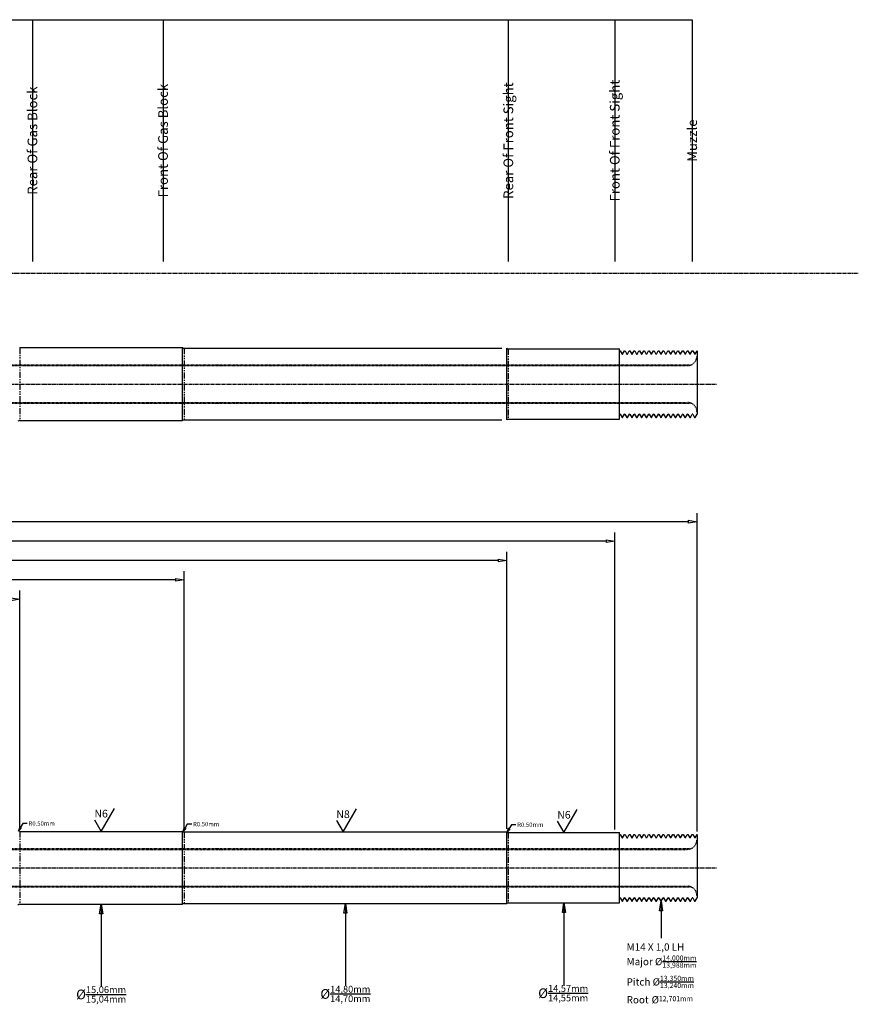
# Model space of a CAD drawing. Units: inches. Extents: x -1 to 483, y -54 to 185.
# Drawn here: x 310 to 483, y -18 to 185 of the extents above; entities that cross this region are included whole.
import ezdxf
from ezdxf.enums import TextEntityAlignment as Align

# ---------------------------------------------------------------- set-up
doc = ezdxf.new("R2010")
doc.units = ezdxf.units.IN
doc.header["$MEASUREMENT"] = 0
for name, pattern in [('CENTER2', [1.125, 0.75, -0.125, 0.125, -0.125]), ('HIDDEN2', [0.1875, 0.125, -0.0625]), ('PHANTOM', [2.5, 1.25, -0.25, 0.25, -0.25, 0.25, -0.25])]:
    doc.linetypes.add(name, pattern=pattern)
for name, color, linetype in [('CENTERLINE', 1, 'CENTER2'), ('HIDDEN', 5, 'HIDDEN2'), ('PHANTOM', 252, 'PHANTOM'), ('TEXT', 5, 'Continuous')]:
    doc.layers.add(name, color=color, linetype=linetype)
doc.dimstyles.get("Standard").update_dxf_attribs({"dimtxt": 0.18, "dimasz": 0.18, "dimexe": 0.18, "dimexo": 0.0625, "dimgap": 0.09, "dimtad": 0, "dimtih": 1, "dimtoh": 1, "dimdec": 4, "dimzin": 0, "dimdsep": 46, "dimtxsty": 'Standard', "dimcen": 0.09, "dimadec": 0, "dimazin": 0, "dimtfac": 1, "dimtdec": 4, "dimtofl": 0, "dimtmove": 0, "dimatfit": 3, "dimfxl": 0, "dimtolj": 1, "dimtzin": 0, "dimarcsym": 0})
doc.dimstyles.new('Standard$0', dxfattribs={"dimtxt": 0.18, "dimasz": 0.18, "dimexe": 0.18, "dimexo": 0.0625, "dimgap": 0.09, "dimtad": 0, "dimtih": 1, "dimtoh": 1, "dimdec": 4, "dimzin": 4, "dimdsep": 46, "dimtxsty": 'Standard', "dimcen": 0.09, "dimadec": 5, "dimazin": 1, "dimtfac": 1, "dimtdec": 4, "dimtofl": 0, "dimtmove": 0, "dimatfit": 3, "dimfxl": 0, "dimtolj": 1, "dimtzin": 0, "dimarcsym": 0})

# ---------------------------------------------------------------- blocks, each defined once
blk = doc.blocks.new('_ClosedBlank')
at = {"color": 0, "linetype": 'ByBlock', "lineweight": -2}
for p, q in [((-1, 0.17), (0, 0)), ((-1, 0.17), (-1, -0.17)), ((0, 0), (-1, -0.17))]:
    blk.add_line(p, q, dxfattribs=at)
blk = doc.blocks.new('*D12')
at = {"color": 0, "lineweight": -2}
for p, q in [((34.79, 20.8), (34.79, 83.23)), ((36.59, 81.43), (236.44, 81.43)), ((447.99, 81.43), (248.14, 81.43)), ((449.79, 17.42), (449.79, 83.23))]:
    blk.add_line(p, q, dxfattribs=at)
at = {"layer": 'Defpoints', "color": 0}
for p in [(449.79, 81.43), (34.79, 20.18), (449.79, 16.8)]:
    blk.add_point(p, dxfattribs=at)
at = {"color": 0, "lineweight": -2, "xscale": 1.8, "yscale": 1.8, "zscale": 1.8, "rotation": 180}
blk.add_blockref('_ClosedBlank', (34.79, 81.43), dxfattribs=at)
at = {"color": 0, "lineweight": -2, "xscale": 1.8, "yscale": 1.8, "zscale": 1.8}
blk.add_blockref('_ClosedBlank', (449.79, 81.43), dxfattribs=at)
at = {"color": 0, "insert": (242.29, 81.43), "char_height": 1.8, "attachment_point": 5}
blk.add_mtext('\\A1;415.0mm', dxfattribs=at)
blk = doc.blocks.new('*D7')
at = {"color": 0, "lineweight": -2}
for p, q in [((34.79, 20.8), (34.79, 67.23)), ((309.79, 18.06), (309.79, 67.23)), ((36.59, 65.43), (166.14, 65.43)), ((307.99, 65.43), (178.44, 65.43))]:
    blk.add_line(p, q, dxfattribs=at)
at = {"layer": 'Defpoints', "color": 0}
for p in [(34.79, 65.43), (34.79, 20.18), (309.79, 17.43)]:
    blk.add_point(p, dxfattribs=at)
at = {"color": 0, "lineweight": -2, "xscale": 1.8, "yscale": 1.8, "zscale": 1.8, "rotation": 180}
blk.add_blockref('_ClosedBlank', (34.79, 65.43), dxfattribs=at)
at = {"color": 0, "lineweight": -2, "xscale": 1.8, "yscale": 1.8, "zscale": 1.8}
blk.add_blockref('_ClosedBlank', (309.79, 65.43), dxfattribs=at)
at = {"color": 0, "insert": (172.29, 65.43), "char_height": 1.8, "attachment_point": 5}
blk.add_mtext('\\A1;275.0mm', dxfattribs=at)
blk = doc.blocks.new('*D8')
at = {"color": 0, "lineweight": -2}
for p, q in [((34.79, 20.8), (34.79, 71.23)), ((36.59, 69.43), (183.29, 69.43)), ((341.99, 69.43), (195.29, 69.43)), ((343.79, 17.93), (343.79, 71.23))]:
    blk.add_line(p, q, dxfattribs=at)
at = {"layer": 'Defpoints', "color": 0}
for p in [(34.79, 69.43), (34.79, 20.18), (343.79, 17.31)]:
    blk.add_point(p, dxfattribs=at)
at = {"color": 0, "lineweight": -2, "xscale": 1.8, "yscale": 1.8, "zscale": 1.8, "rotation": 180}
blk.add_blockref('_ClosedBlank', (34.79, 69.43), dxfattribs=at)
at = {"color": 0, "lineweight": -2, "xscale": 1.8, "yscale": 1.8, "zscale": 1.8}
blk.add_blockref('_ClosedBlank', (343.79, 69.43), dxfattribs=at)
at = {"color": 0, "insert": (189.29, 69.43), "char_height": 1.8, "attachment_point": 5}
blk.add_mtext('\\A1;309.0mm', dxfattribs=at)
blk = doc.blocks.new('*D9')
at = {"color": 0, "lineweight": -2}
for p, q in [((34.79, 20.8), (34.79, 75.23)), ((36.59, 73.43), (216.33, 73.43)), ((408.66, 73.43), (228.93, 73.43)), ((410.46, 17.93), (410.46, 75.23))]:
    blk.add_line(p, q, dxfattribs=at)
at = {"layer": 'Defpoints', "color": 0}
for p in [(34.79, 73.43), (34.79, 20.18), (410.46, 17.31)]:
    blk.add_point(p, dxfattribs=at)
at = {"color": 0, "lineweight": -2, "xscale": 1.8, "yscale": 1.8, "zscale": 1.8, "rotation": 180}
blk.add_blockref('_ClosedBlank', (34.79, 73.43), dxfattribs=at)
at = {"color": 0, "lineweight": -2, "xscale": 1.8, "yscale": 1.8, "zscale": 1.8}
blk.add_blockref('_ClosedBlank', (410.46, 73.43), dxfattribs=at)
at = {"color": 0, "insert": (222.63, 73.43), "char_height": 1.8, "attachment_point": 5}
blk.add_mtext('\\A1;375.7mm', dxfattribs=at)
blk = doc.blocks.new('*D10')
at = {"color": 0, "lineweight": -2}
for p, q in [((34.79, 20.8), (34.79, 79.23)), ((36.59, 77.43), (227.64, 77.43)), ((430.99, 77.43), (239.94, 77.43)), ((432.79, 17.81), (432.79, 79.23))]:
    blk.add_line(p, q, dxfattribs=at)
at = {"layer": 'Defpoints', "color": 0}
for p in [(432.79, 77.43), (34.79, 20.18), (432.79, 17.18)]:
    blk.add_point(p, dxfattribs=at)
at = {"color": 0, "lineweight": -2, "xscale": 1.8, "yscale": 1.8, "zscale": 1.8, "rotation": 180}
blk.add_blockref('_ClosedBlank', (34.79, 77.43), dxfattribs=at)
at = {"color": 0, "lineweight": -2, "xscale": 1.8, "yscale": 1.8, "zscale": 1.8}
blk.add_blockref('_ClosedBlank', (432.79, 77.43), dxfattribs=at)
at = {"color": 0, "insert": (233.79, 77.43), "char_height": 1.8, "attachment_point": 5}
blk.add_mtext('\\A1;398.0mm', dxfattribs=at)
blk = doc.blocks.new('*D21')
at = {"color": 0, "lineweight": -2}
for p, q in [((310.44, 19.06), (309.99, 18.28)), ((311.34, 19.06), (310.44, 19.06))]:
    blk.add_line(p, q, dxfattribs=at)
at = {"layer": 'Defpoints', "color": 0}
for p in [(309.54, 17.5), (309.79, 17.93)]:
    blk.add_point(p, dxfattribs=at)
at = {"color": 0, "lineweight": -2, "xscale": 0.8999999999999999, "yscale": 0.8999999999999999, "zscale": 0.8999999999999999, "rotation": 240.0000000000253}
blk.add_blockref('_ClosedBlank', (309.54, 17.5), dxfattribs=at)
at = {"color": 0, "insert": (314.34, 19.06), "char_height": 0.9, "attachment_point": 5}
blk.add_mtext('\\A1;R0.50mm', dxfattribs=at)
blk = doc.blocks.new('*D22')
at = {"color": 0, "lineweight": -2}
for p, q in [((344.44, 18.93), (343.99, 18.15)), ((345.34, 18.93), (344.44, 18.93))]:
    blk.add_line(p, q, dxfattribs=at)
at = {"layer": 'Defpoints', "color": 0}
for p in [(343.54, 17.37), (343.79, 17.81)]:
    blk.add_point(p, dxfattribs=at)
at = {"color": 0, "lineweight": -2, "xscale": 0.8999999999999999, "yscale": 0.8999999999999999, "zscale": 0.8999999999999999, "rotation": 240.0000000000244}
blk.add_blockref('_ClosedBlank', (343.54, 17.37), dxfattribs=at)
at = {"color": 0, "insert": (348.34, 18.93), "char_height": 0.9, "attachment_point": 5}
blk.add_mtext('\\A1;R0.50mm', dxfattribs=at)
blk = doc.blocks.new('*D23')
at = {"color": 0, "lineweight": -2}
for p, q in [((411.44, 18.81), (410.99, 18.03)), ((412.34, 18.81), (411.44, 18.81))]:
    blk.add_line(p, q, dxfattribs=at)
at = {"layer": 'Defpoints', "color": 0}
for p in [(410.54, 17.25), (410.79, 17.68)]:
    blk.add_point(p, dxfattribs=at)
at = {"color": 0, "lineweight": -2, "xscale": 0.8999999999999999, "yscale": 0.8999999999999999, "zscale": 0.8999999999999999, "rotation": 239.9999999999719}
blk.add_blockref('_ClosedBlank', (410.54, 17.25), dxfattribs=at)
at = {"color": 0, "insert": (415.34, 18.81), "char_height": 0.9, "attachment_point": 5}
blk.add_mtext('\\A1;R0.50mm', dxfattribs=at)

msp = doc.modelspace()

# ---------------------------------------------------------------- linework, layer by layer
for p, q in [((6.79168, 185.23005), (448.79168, 185.23005)), ((312.42168, 185.23005), (312.42168, 135.23005)), ((339.42168, 185.23005), (339.42168, 135.23005)), ((410.79168, 185.23005), (410.79168, 135.23005)), ((432.79168, 185.23005), (432.79168, 135.23005)), ((448.79168, 185.23005), (448.79168, 135.23005)), ((309.79168, 117.43025), (343.46096, 117.43025)), ((343.46096, 102.38025), (343.46096, 117.43025)), ((343.79168, 117.30525), (409.46096, 117.30525)), ((410.46096, 102.50525), (410.46096, 117.30525)), ((410.79168, 117.18025), (433.79168, 117.18025)), ((433.79168, 102.63025), (433.79168, 117.18025)), ((433.79168, 116.79699), (433.91668, 116.79699)), ((433.91668, 116.79699), (434.31251, 116.11139)), ((434.29168, 116.14747), (434.31251, 116.11139)), ((434.31251, 116.11139), (434.39585, 116.11139)), ((434.39585, 116.11139), (434.31251, 116.11139)), ((434.39585, 116.11139), (434.79168, 116.79699)), ((434.79168, 116.79699), (434.91668, 116.79699)), ((434.91668, 116.79699), (435.31251, 116.11139)), ((435.29168, 116.14747), (435.31251, 116.11139)), ((435.31251, 116.11139), (435.39585, 116.11139)), ((435.39585, 116.11139), (435.31251, 116.11139)), ((435.39585, 116.11139), (435.79168, 116.79699)), ((435.79168, 116.79699), (435.91668, 116.79699)), ((435.91668, 116.79699), (436.31251, 116.11139)), ((436.29168, 116.14747), (436.31251, 116.11139)), ((436.31251, 116.11139), (436.39585, 116.11139)), ((436.39585, 116.11139), (436.31251, 116.11139)), ((436.39585, 116.11139), (436.79168, 116.79699)), ((436.79168, 116.79699), (436.91668, 116.79699)), ((436.91668, 116.79699), (437.31251, 116.11139)), ((437.29168, 116.14747), (437.31251, 116.11139)), ((437.31251, 116.11139), (437.39585, 116.11139)), ((437.39585, 116.11139), (437.31251, 116.11139)), ((437.39585, 116.11139), (437.79168, 116.79699)), ((437.79168, 116.79699), (437.91668, 116.79699)), ((437.91668, 116.79699), (438.31251, 116.11139)), ((438.31251, 116.11139), (438.39585, 116.11139)), ((438.39585, 116.11139), (438.31251, 116.11139)), ((438.39585, 116.11139), (438.79168, 116.79699)), ((438.79168, 116.79699), (438.91668, 116.79699)), ((438.91668, 116.79699), (439.31251, 116.11139)), ((439.39585, 116.11139), (439.31251, 116.11139)), ((439.39585, 116.11139), (439.79168, 116.79699)), ((439.79168, 116.79699), (439.91668, 116.79699)), ((439.91668, 116.79699), (440.31251, 116.11139)), ((440.39585, 116.11139), (440.31251, 116.11139)), ((440.39585, 116.11139), (440.79168, 116.79699)), ((440.79168, 116.79699), (440.91668, 116.79699)), ((440.91668, 116.79699), (441.31251, 116.11139)), ((441.39585, 116.11139), (441.31251, 116.11139)), ((441.39585, 116.11139), (441.79168, 116.79699)), ((441.79168, 116.79699), (441.91668, 116.79699)), ((441.91668, 116.79699), (442.31251, 116.11139)), ((442.39585, 116.11139), (442.31251, 116.11139)), ((442.39585, 116.11139), (442.79168, 116.79699)), ((442.79168, 116.79699), (442.91668, 116.79699)), ((442.91668, 116.79699), (443.31251, 116.11139)), ((443.39585, 116.11139), (443.31251, 116.11139)), ((443.39585, 116.11139), (443.79168, 116.79699)), ((443.79168, 116.79699), (443.91668, 116.79699)), ((443.91668, 116.79699), (444.31251, 116.11139)), ((444.39585, 116.11139), (444.31251, 116.11139)), ((444.39585, 116.11139), (444.79168, 116.79699)), ((444.79168, 116.79699), (444.91668, 116.79699)), ((444.91668, 116.79699), (445.31251, 116.11139)), ((445.39585, 116.11139), (445.31251, 116.11139)), ((445.39585, 116.11139), (445.79168, 116.79699)), ((445.79168, 116.79699), (445.91668, 116.79699)), ((445.91668, 116.79699), (446.31251, 116.11139)), ((446.39585, 116.11139), (446.31251, 116.11139)), ((446.39585, 116.11139), (446.79168, 116.79699)), ((446.79168, 116.79699), (446.91668, 116.79699)), ((446.91668, 116.79699), (447.31251, 116.11139)), ((447.39585, 116.11139), (447.31251, 116.11139)), ((447.39585, 116.11139), (447.79168, 116.79699)), ((447.79168, 116.79699), (447.91668, 116.79699)), ((447.91668, 116.79699), (448.31251, 116.11139)), ((448.39585, 116.11139), (448.31251, 116.11139)), ((448.39585, 116.11139), (448.79168, 116.79699)), ((448.79168, 116.79699), (448.91668, 116.79699)), ((448.91668, 116.79699), (449.31251, 116.11139)), ((449.39585, 116.11139), (449.31251, 116.11139)), ((449.39585, 116.11139), (449.79168, 116.79699)), ((449.79168, 116.79699), (449.79168, 103.66302)), ((309.79168, 102.38025), (343.46096, 102.38025)), ((343.79168, 102.50525), (409.46096, 102.50525)), ((410.79168, 102.63025), (433.79168, 102.63025)), ((433.79168, 103.66302), (433.81251, 103.6991)), ((433.81251, 103.6991), (433.89585, 103.6991)), ((433.89585, 103.6991), (433.81251, 103.6991)), ((433.89585, 103.6991), (434.29168, 103.0135)), ((434.29168, 103.0135), (434.41668, 103.0135)), ((434.41668, 103.0135), (434.81251, 103.6991)), ((434.81251, 103.6991), (434.89585, 103.6991)), ((434.89585, 103.6991), (434.81251, 103.6991)), ((434.89585, 103.6991), (435.29168, 103.0135)), ((435.29168, 103.0135), (435.41668, 103.0135)), ((435.41668, 103.0135), (435.81251, 103.6991)), ((435.81251, 103.6991), (435.89585, 103.6991)), ((435.89585, 103.6991), (435.81251, 103.6991)), ((435.89585, 103.6991), (436.29168, 103.0135)), ((436.29168, 103.0135), (436.41668, 103.0135)), ((436.41668, 103.0135), (436.81251, 103.6991)), ((436.81251, 103.6991), (436.89585, 103.6991)), ((436.89585, 103.6991), (436.81251, 103.6991)), ((436.89585, 103.6991), (437.29168, 103.0135)), ((437.29168, 103.0135), (437.41668, 103.0135)), ((437.41668, 103.0135), (437.81251, 103.6991)), ((437.81251, 103.6991), (437.89585, 103.6991)), ((437.89585, 103.6991), (437.81251, 103.6991)), ((437.89585, 103.6991), (438.29168, 103.0135)), ((438.29168, 103.0135), (438.41668, 103.0135)), ((438.41668, 103.0135), (438.81251, 103.6991)), ((438.89585, 103.6991), (438.81251, 103.6991)), ((438.89585, 103.6991), (439.29168, 103.0135)), ((439.29168, 103.0135), (439.41668, 103.0135)), ((439.41668, 103.0135), (439.81251, 103.6991)), ((439.89585, 103.6991), (439.81251, 103.6991)), ((439.89585, 103.6991), (440.29168, 103.0135)), ((440.29168, 103.0135), (440.41668, 103.0135)), ((440.41668, 103.0135), (440.81251, 103.6991)), ((440.89585, 103.6991), (440.81251, 103.6991)), ((440.89585, 103.6991), (441.29168, 103.0135)), ((441.29168, 103.0135), (441.41668, 103.0135)), ((441.41668, 103.0135), (441.81251, 103.6991)), ((441.89585, 103.6991), (441.81251, 103.6991)), ((441.89585, 103.6991), (442.29168, 103.0135)), ((442.29168, 103.0135), (442.41668, 103.0135)), ((442.41668, 103.0135), (442.81251, 103.6991)), ((442.89585, 103.6991), (442.81251, 103.6991)), ((442.89585, 103.6991), (443.29168, 103.0135)), ((443.29168, 103.0135), (443.41668, 103.0135)), ((443.41668, 103.0135), (443.81251, 103.6991)), ((443.89585, 103.6991), (443.81251, 103.6991)), ((443.89585, 103.6991), (444.29168, 103.0135)), ((444.29168, 103.0135), (444.41668, 103.0135)), ((444.41668, 103.0135), (444.81251, 103.6991)), ((444.89585, 103.6991), (444.81251, 103.6991)), ((444.89585, 103.6991), (445.29168, 103.0135)), ((445.29168, 103.0135), (445.41668, 103.0135)), ((445.41668, 103.0135), (445.81251, 103.6991)), ((445.89585, 103.6991), (445.81251, 103.6991)), ((445.89585, 103.6991), (446.29168, 103.0135)), ((446.29168, 103.0135), (446.41668, 103.0135)), ((446.41668, 103.0135), (446.81251, 103.6991)), ((446.89585, 103.6991), (446.81251, 103.6991)), ((446.89585, 103.6991), (447.29168, 103.0135)), ((447.29168, 103.0135), (447.41668, 103.0135)), ((447.41668, 103.0135), (447.81251, 103.6991)), ((447.89585, 103.6991), (447.81251, 103.6991)), ((447.89585, 103.6991), (448.29168, 103.0135)), ((448.29168, 103.0135), (448.41668, 103.0135)), ((448.41668, 103.0135), (448.81251, 103.6991)), ((448.89585, 103.6991), (448.81251, 103.6991)), ((448.89585, 103.6991), (449.29168, 103.0135)), ((449.29168, 103.0135), (449.41668, 103.0135)), ((449.41668, 103.0135), (449.79168, 103.66302)), ((326.62632, 17.43025), (329.37595, 22.19275)), ((376.62632, 17.30525), (379.37595, 22.06775)), ((422.29168, 17.18025), (425.04131, 21.94275)), ((325.2515, 19.8115), (326.62632, 17.43025)), ((375.2515, 19.6865), (376.62632, 17.30525)), ((420.91686, 19.5615), (422.29168, 17.18025)), ((309.79168, 17.43025), (343.46096, 17.43025)), ((343.46096, 2.38025), (343.46096, 17.43025)), ((343.79168, 17.30525), (410.46096, 17.30525)), ((410.46096, 2.50525), (410.46096, 17.30525)), ((410.79168, 17.18025), (433.79168, 17.18025)), ((433.79168, 2.63025), (433.79168, 17.18025)), ((433.79168, 16.79699), (433.91668, 16.79699)), ((433.91668, 16.79699), (434.31251, 16.11139)), ((434.39585, 16.11139), (434.79168, 16.79699)), ((434.79168, 16.79699), (434.91668, 16.79699)), ((434.91668, 16.79699), (435.31251, 16.11139)), ((435.39585, 16.11139), (435.79168, 16.79699)), ((435.79168, 16.79699), (435.91668, 16.79699)), ((435.91668, 16.79699), (436.31251, 16.11139)), ((436.39585, 16.11139), (436.79168, 16.79699)), ((436.79168, 16.79699), (436.91668, 16.79699)), ((436.91668, 16.79699), (437.31251, 16.11139)), ((437.39585, 16.11139), (437.79168, 16.79699)), ((437.79168, 16.79699), (437.91668, 16.79699)), ((437.91668, 16.79699), (438.31251, 16.11139)), ((438.39585, 16.11139), (438.79168, 16.79699)), ((438.79168, 16.79699), (438.91668, 16.79699)), ((438.91668, 16.79699), (439.31251, 16.11139)), ((439.39585, 16.11139), (439.79168, 16.79699)), ((439.79168, 16.79699), (439.91668, 16.79699)), ((439.91668, 16.79699), (440.31251, 16.11139)), ((440.39585, 16.11139), (440.79168, 16.79699)), ((440.79168, 16.79699), (440.91668, 16.79699)), ((440.91668, 16.79699), (441.31251, 16.11139)), ((441.39585, 16.11139), (441.79168, 16.79699)), ((441.79168, 16.79699), (441.91668, 16.79699)), ((441.91668, 16.79699), (442.31251, 16.11139)), ((442.39585, 16.11139), (442.79168, 16.79699)), ((442.79168, 16.79699), (442.91668, 16.79699)), ((442.91668, 16.79699), (443.31251, 16.11139)), ((443.39585, 16.11139), (443.79168, 16.79699)), ((443.79168, 16.79699), (443.91668, 16.79699)), ((443.91668, 16.79699), (444.31251, 16.11139)), ((444.39585, 16.11139), (444.79168, 16.79699)), ((444.79168, 16.79699), (444.91668, 16.79699)), ((444.91668, 16.79699), (445.31251, 16.11139)), ((445.39585, 16.11139), (445.79168, 16.79699)), ((445.79168, 16.79699), (445.91668, 16.79699)), ((445.91668, 16.79699), (446.31251, 16.11139)), ((446.39585, 16.11139), (446.79168, 16.79699)), ((446.79168, 16.79699), (446.91668, 16.79699)), ((446.91668, 16.79699), (447.31251, 16.11139)), ((447.39585, 16.11139), (447.79168, 16.79699)), ((447.79168, 16.79699), (447.91668, 16.79699)), ((447.91668, 16.79699), (448.31251, 16.11139)), ((448.39585, 16.11139), (448.79168, 16.79699)), ((448.79168, 16.79699), (448.91668, 16.79699)), ((448.91668, 16.79699), (449.31251, 16.11139)), ((449.39585, 16.11139), (449.79168, 16.79699)), ((449.79168, 16.79699), (449.79168, 3.66302)), ((434.29168, 16.14747), (434.31251, 16.11139)), ((434.31251, 16.11139), (434.39585, 16.11139)), ((434.39585, 16.11139), (434.31251, 16.11139)), ((435.29168, 16.14747), (435.31251, 16.11139)), ((435.31251, 16.11139), (435.39585, 16.11139)), ((435.39585, 16.11139), (435.31251, 16.11139)), ((436.29168, 16.14747), (436.31251, 16.11139)), ((436.31251, 16.11139), (436.39585, 16.11139)), ((436.39585, 16.11139), (436.31251, 16.11139)), ((437.29168, 16.14747), (437.31251, 16.11139)), ((437.31251, 16.11139), (437.39585, 16.11139)), ((437.39585, 16.11139), (437.31251, 16.11139)), ((438.31251, 16.11139), (438.39585, 16.11139)), ((438.39585, 16.11139), (438.31251, 16.11139)), ((439.39585, 16.11139), (439.31251, 16.11139)), ((440.39585, 16.11139), (440.31251, 16.11139)), ((441.39585, 16.11139), (441.31251, 16.11139)), ((442.39585, 16.11139), (442.31251, 16.11139)), ((443.39585, 16.11139), (443.31251, 16.11139)), ((444.39585, 16.11139), (444.31251, 16.11139)), ((445.39585, 16.11139), (445.31251, 16.11139)), ((446.39585, 16.11139), (446.31251, 16.11139)), ((447.39585, 16.11139), (447.31251, 16.11139)), ((448.39585, 16.11139), (448.31251, 16.11139)), ((449.39585, 16.11139), (449.31251, 16.11139)), ((309.79168, 2.38025), (343.46096, 2.38025)), ((343.79168, 2.50525), (410.46096, 2.50525)), ((410.79168, 2.63025), (433.79168, 2.63025)), ((433.79168, 3.66302), (433.81251, 3.6991)), ((433.81251, 3.6991), (433.89585, 3.6991)), ((433.89585, 3.6991), (433.81251, 3.6991)), ((433.89585, 3.6991), (434.29168, 3.0135)), ((434.29168, 3.0135), (434.41668, 3.0135)), ((434.41668, 3.0135), (434.81251, 3.6991)), ((434.81251, 3.6991), (434.89585, 3.6991)), ((434.89585, 3.6991), (434.81251, 3.6991)), ((434.89585, 3.6991), (435.29168, 3.0135)), ((435.29168, 3.0135), (435.41668, 3.0135)), ((435.41668, 3.0135), (435.81251, 3.6991)), ((435.81251, 3.6991), (435.89585, 3.6991)), ((435.89585, 3.6991), (435.81251, 3.6991)), ((435.89585, 3.6991), (436.29168, 3.0135)), ((436.29168, 3.0135), (436.41668, 3.0135)), ((436.41668, 3.0135), (436.81251, 3.6991)), ((436.81251, 3.6991), (436.89585, 3.6991)), ((436.89585, 3.6991), (436.81251, 3.6991)), ((436.89585, 3.6991), (437.29168, 3.0135)), ((437.29168, 3.0135), (437.41668, 3.0135)), ((437.41668, 3.0135), (437.81251, 3.6991)), ((437.81251, 3.6991), (437.89585, 3.6991)), ((437.89585, 3.6991), (437.81251, 3.6991)), ((437.89585, 3.6991), (438.29168, 3.0135)), ((438.29168, 3.0135), (438.41668, 3.0135)), ((438.41668, 3.0135), (438.81251, 3.6991)), ((438.89585, 3.6991), (438.81251, 3.6991)), ((438.89585, 3.6991), (439.29168, 3.0135)), ((439.29168, 3.0135), (439.41668, 3.0135)), ((439.41668, 3.0135), (439.81251, 3.6991)), ((439.89585, 3.6991), (439.81251, 3.6991)), ((439.89585, 3.6991), (440.29168, 3.0135)), ((440.29168, 3.0135), (440.41668, 3.0135)), ((440.41668, 3.0135), (440.81251, 3.6991)), ((440.89585, 3.6991), (440.81251, 3.6991)), ((440.89585, 3.6991), (441.29168, 3.0135)), ((441.29168, 3.0135), (441.41668, 3.0135)), ((441.41668, 3.0135), (441.81251, 3.6991)), ((441.89585, 3.6991), (441.81251, 3.6991)), ((441.89585, 3.6991), (442.29168, 3.0135)), ((442.29168, 3.0135), (442.41668, 3.0135)), ((442.41668, 3.0135), (442.81251, 3.6991)), ((442.89585, 3.6991), (442.81251, 3.6991)), ((442.89585, 3.6991), (443.29168, 3.0135)), ((443.29168, 3.0135), (443.41668, 3.0135)), ((443.41668, 3.0135), (443.81251, 3.6991)), ((443.89585, 3.6991), (443.81251, 3.6991)), ((443.89585, 3.6991), (444.29168, 3.0135)), ((444.29168, 3.0135), (444.41668, 3.0135)), ((444.41668, 3.0135), (444.81251, 3.6991)), ((444.89585, 3.6991), (444.81251, 3.6991)), ((444.89585, 3.6991), (445.29168, 3.0135)), ((445.29168, 3.0135), (445.41668, 3.0135)), ((445.41668, 3.0135), (445.81251, 3.6991)), ((445.89585, 3.6991), (445.81251, 3.6991)), ((445.89585, 3.6991), (446.29168, 3.0135)), ((446.29168, 3.0135), (446.41668, 3.0135)), ((446.41668, 3.0135), (446.81251, 3.6991)), ((446.89585, 3.6991), (446.81251, 3.6991)), ((446.89585, 3.6991), (447.29168, 3.0135)), ((447.29168, 3.0135), (447.41668, 3.0135)), ((447.41668, 3.0135), (447.81251, 3.6991)), ((447.89585, 3.6991), (447.81251, 3.6991)), ((447.89585, 3.6991), (448.29168, 3.0135)), ((448.29168, 3.0135), (448.41668, 3.0135)), ((448.41668, 3.0135), (448.81251, 3.6991)), ((448.89585, 3.6991), (448.81251, 3.6991)), ((448.89585, 3.6991), (449.29168, 3.0135)), ((449.29168, 3.0135), (449.41668, 3.0135)), ((449.41668, 3.0135), (449.79168, 3.66302))]:
    msp.add_line(p, q)
for centre, start, end in [((343.79168, 117.80525), 228.5903779, 270), ((410.79168, 117.68025), 228.5903779, 270), ((309.79168, 101.88025), 90, 139.4583981), ((343.79168, 102.0043), 90, 131.2457175), ((410.79168, 102.13025), 90, 131.4096221), ((343.79168, 17.80525), 228.5903779, 270), ((410.79168, 17.68025), 228.5903779, 270), ((309.79168, 1.88025), 90, 139.4583981), ((343.79168, 2.00525), 90, 131.4096221), ((410.79168, 2.13025), 90, 131.4096221)]:
    msp.add_arc(centre, 0.5, start, end)
at = {"layer": 'CENTERLINE'}
for p, q in [((59.13134, 132.8543), (483.13134, 132.8543)), ((29.79168, 109.90525), (453.79168, 109.90525)), ((29.79168, 9.90525), (453.79168, 9.90525))]:
    msp.add_line(p, q, dxfattribs=at)
at = {"layer": 'HIDDEN'}
for p, q in [((69.37422, 113.86765), (448.55743, 113.86765)), ((69.52662, 113.71525), (447.79168, 113.71525)), ((69.37428, 105.94285), (448.55743, 105.94285)), ((69.52668, 106.09525), (447.79168, 106.09525)), ((69.37422, 13.86765), (448.55743, 13.86765)), ((69.52662, 13.71525), (447.79168, 13.71525)), ((69.37428, 5.94285), (448.55743, 5.94285)), ((69.52668, 6.09525), (447.79168, 6.09525))]:
    msp.add_line(p, q, dxfattribs=at)
for centre, start, end in [((447.79168, 115.71525), 270, 0), ((447.79168, 104.09525), 0, 90), ((447.79168, 15.71525), 270, 0), ((447.79168, 4.09525), 0, 90)]:
    msp.add_arc(centre, 2, start, end, dxfattribs=at)
at = {"layer": 'PHANTOM'}
for p, q in [((309.79168, 117.43025), (309.79168, 102.38025)), ((343.79168, 117.30525), (343.79168, 102.50525)), ((410.79168, 117.18025), (410.79168, 102.63025)), ((309.79168, 17.43025), (309.79168, 2.38025)), ((343.79168, 17.30525), (343.79168, 2.50525)), ((410.79168, 17.18025), (410.79168, 2.63025))]:
    msp.add_line(p, q, dxfattribs=at)

# ---------------------------------------------------------------- texts
for s, p in [('Rear Of Gas Block', (312.42168, 160.23005)), ('Front Of Gas Block', (339.42168, 160.23005)), ('Rear Of Front Sight', (410.79168, 160.23005)), ('Front Of Front Sight', (432.79168, 160.23005)), ('Muzzle', (448.79168, 160.23005))]:
    msp.add_text(s, height=2, rotation=90).set_placement(p, align=Align.MIDDLE_CENTER)
for s, p in [('N6', (326.62632, 19.8115)), ('N8', (376.62632, 19.6865)), ('N6', (422.29168, 19.5615))]:
    msp.add_text(s, height=1.5875).set_placement(p, align=Align.BOTTOM_CENTER)
at = {"char_height": 2, "width": 10.5482646, "attachment_point": 2}
for s, insert in [('\\A1;%%C{\\H0.7x;\\S15,06mm/15,04mm;}', (326.62632, -14.59475)), ('\\A1;%%C{\\H0.7x;\\S14,80mm/14,70mm;}', (377.10508, -14.49475)), ('\\A1;%%C{\\H0.7x;\\S14,57mm/14,55mm;}', (422.13361, -14.34475))]:
    msp.add_mtext(s, dxfattribs=dict(at, insert=insert))
at = {"layer": 'TEXT', "color": 7, "insert": (435.24373, -5.72384), "char_height": 2, "width": 19.3860592, "attachment_point": 1}
msp.add_mtext('\\A1;{\\H0.75x;M14 X 1,0 LH\\PMajor %%C\\H0.7x;\\S14,000mm/13,988mm;\\H1.429x;\\PPitch %%C\\H0.7x;\\S13,350mm/13,240mm;\\H1.429x;\\PRoot} {\\H0.75x;%%C\\H0.7x;12,701mm}', dxfattribs=at)

# ---------------------------------------------------------------- dimensions: what is measured, and where the dimension line sits
for base, p1, p2, picture, middle in [((449.79168, 81.43025), (34.79168, 20.17523), (449.79168, 16.79699), '*D12', (242.29168, 81.43025)), ((432.79168, 77.43025), (34.79168, 20.17523), (432.79168, 17.18025), '*D10', (233.79168, 77.43025)), ((34.79168, 73.43025), (410.46096, 17.30525), (34.79168, 20.17523), '*D9', (222.62632, 73.43025)), ((34.79168, 69.43025), (343.79168, 17.30525), (34.79168, 20.17523), '*D8', (189.29168, 69.43025)), ((34.79168, 65.43025), (309.79168, 17.43025), (34.79168, 20.17523), '*D7', (172.29168, 65.43025))]:
    dim = msp.add_linear_dim(base=base, p1=p1, p2=p2, dimstyle='Standard$0', override={"dimscale": 10, "dimdec": 1, "dimpost": 'mm', "dimblk1": 'ClosedBlank', "dimblk2": 'ClosedBlank', "dimsah": 1})
    dim.commit()
    dim.dimension.update_dxf_attribs({"geometry": picture, "text_midpoint": middle})
for center, mpoint, picture, middle in [((309.79168, 17.93025), (309.54168, 17.49723), '*D21', (310.44168, 19.05608)), ((343.79168, 17.80525), (343.54168, 17.37223), '*D22', (344.44168, 18.93108)), ((410.79168, 17.68025), (410.54168, 17.24723), '*D23', (411.44168, 18.80608))]:
    dim = msp.add_radius_dim(center=center, mpoint=mpoint, dimstyle='Standard', override={"dimscale": 5, "dimdec": 2, "dimpost": 'mm', "dimblk2": 'ClosedBlank', "dimsah": 1, "dimtmove": 1})
    dim.commit()
    dim.dimension.update_dxf_attribs({"geometry": picture, "text_midpoint": middle, "dimtype": 164})

# ---------------------------------------------------------------- leaders
for points, override in [([(326.62632, 2.40525), (326.62632, -14.59475)], {"dimasz": 2, "dimgap": 0.09, "dimtad": 0, "dimldrblk": 'ClosedBlank'}), ([(377.10508, 2.50525), (377.10508, -14.49475)], {"dimasz": 2, "dimgap": 0.09, "dimtad": 0, "dimldrblk": 'ClosedBlank'}), ([(422.29168, 2.63025), (422.29168, -14.36975)], {"dimasz": 2, "dimgap": 0.09, "dimtad": 0, "dimldrblk": 'ClosedBlank'}), ([(442.35418, 3.0135), (442.35418, -4.6355)], {"dimscale": 1, "dimasz": 2, "dimgap": 0.09, "dimtad": 0, "dimldrblk": 'ClosedBlank'})]:
    msp.add_leader(points, dimstyle='Standard', override=override)

doc.saveas('drawing.dxf')
